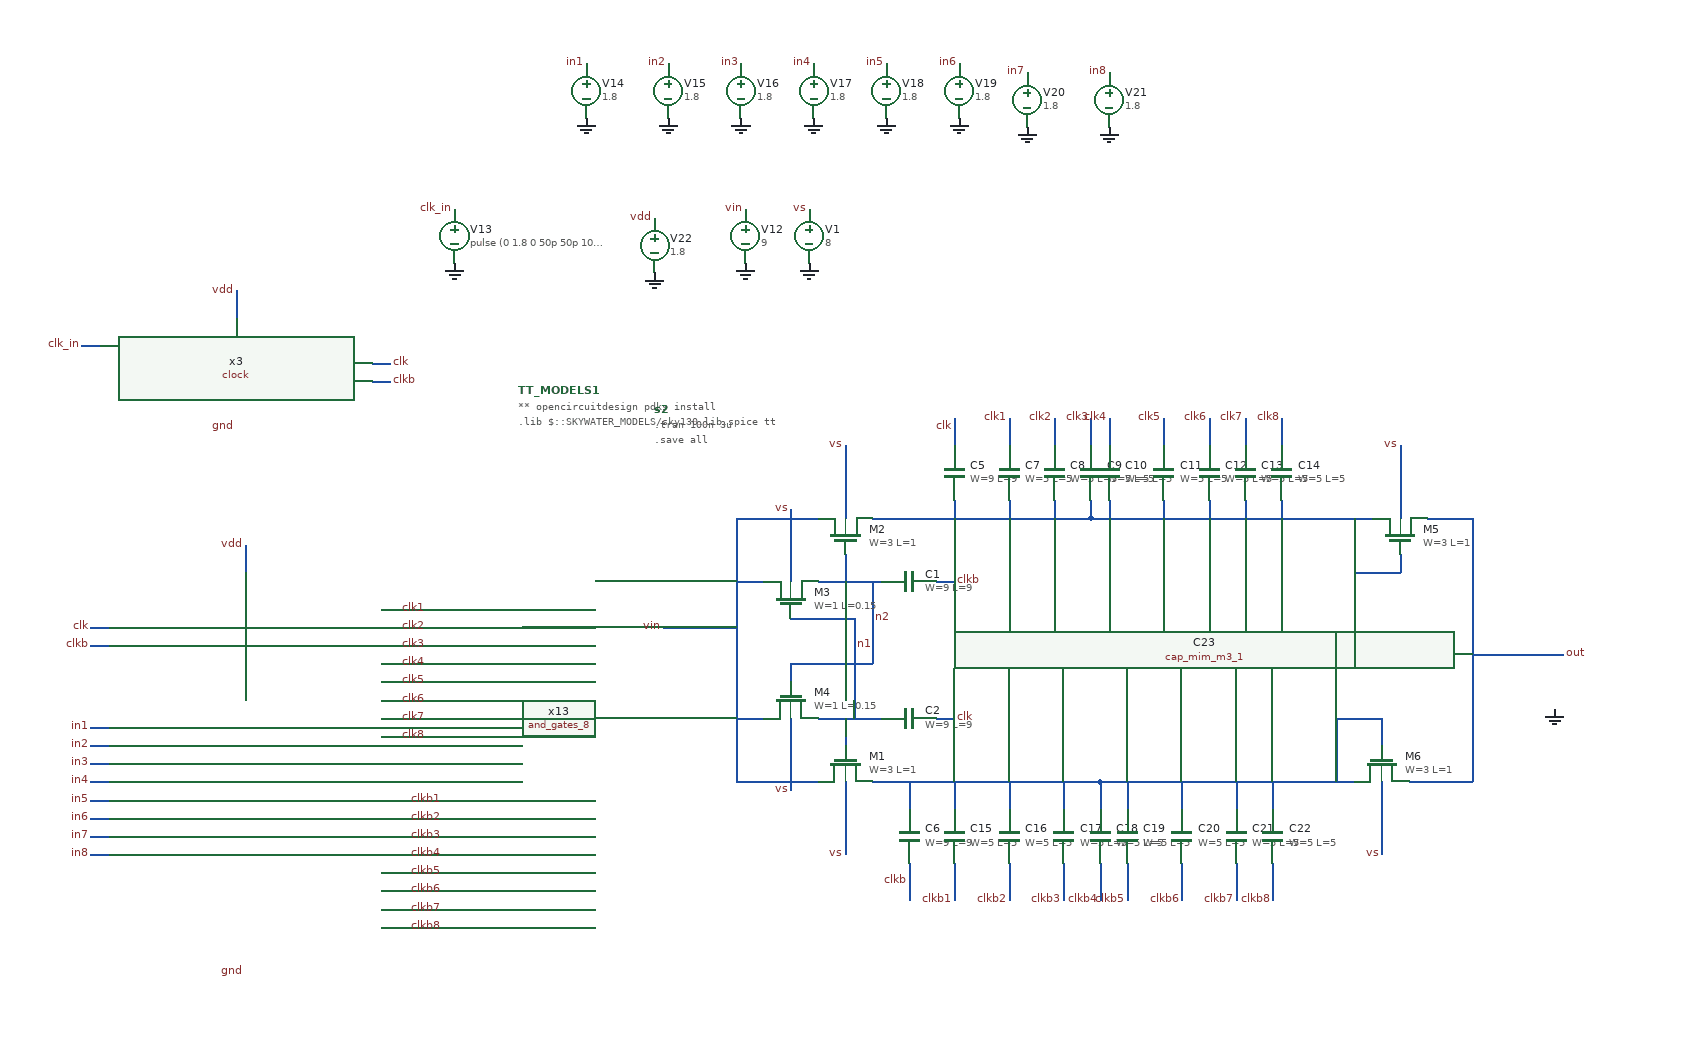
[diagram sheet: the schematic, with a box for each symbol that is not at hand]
v {xschem version=3.4.4 file_version=1.2
}
G {}
K {}
V {}
S {}
E {}
N -100 -80 140 -80 {
lab=#net1}
N -250 -80 -160 -80 {
lab=vin}
N -250 -80 -250 210 {
lab=vin}
N -250 210 -160 210 {
lab=vin}
N -100 210 150 210 {
lab=#net2}
N -250 -10 -220 -10 {
lab=vin}
N -250 140 -220 140 {
lab=vin}
N -160 -10 -90 -10 {
lab=n2}
N -130 -40 -130 -10 {
lab=n2}
N -160 140 -90 140 {
lab=n1}
N -130 140 -130 170 {
lab=n1}
N -10 -100 -10 -80 {
lab=#net1}
N -60 210 -60 240 {
lab=#net2}
N -10 -190 -10 -160 {
lab=clk}
N -60 300 -60 340 {
lab=clkb}
N -30 140 -10 140 {
lab=clk}
N -30 -10 -10 -10 {
lab=clkb}
N -190 30 -120 30 {
lab=n1}
N -120 30 -120 140 {
lab=n1}
N -190 80 -190 100 {
lab=n2}
N -190 80 -100 80 {
lab=n2}
N -100 -10 -100 80 {
lab=n2}
N 140 -80 380 -80 {
lab=#net1}
N 150 210 390 210 {
lab=#net2}
N 50 -100 50 -80 {
lab=#net1}
N 50 -190 50 -160 {
lab=clk1}
N 100 -100 100 -80 {
lab=#net1}
N 100 -190 100 -160 {
lab=clk2}
N 140 -100 140 -80 {
lab=#net1}
N 140 -190 140 -160 {
lab=clk3}
N 160 -100 160 -80 {
lab=#net1}
N 160 -190 160 -160 {
lab=clk4}
N 220 -100 220 -80 {
lab=#net1}
N 220 -190 220 -160 {
lab=clk5}
N 270 -100 270 -80 {
lab=#net1}
N 270 -190 270 -160 {
lab=clk6}
N 310 -100 310 -80 {
lab=#net1}
N 310 -190 310 -160 {
lab=clk7}
N 350 -100 350 -80 {
lab=#net1}
N 350 -190 350 -160 {
lab=clk8}
N -10 210 -10 240 {
lab=#net2}
N -10 300 -10 340 {
lab=clkb1}
N 50 210 50 240 {
lab=#net2}
N 50 300 50 340 {
lab=clkb2}
N 110 210 110 240 {
lab=#net2}
N 110 300 110 340 {
lab=clkb3}
N 150 210 150 240 {
lab=#net2}
N 150 300 150 340 {
lab=clkb4}
N 180 210 180 240 {
lab=#net2}
N 180 300 180 340 {
lab=clkb5}
N 240 210 240 240 {
lab=#net2}
N 240 300 240 340 {
lab=clkb6}
N 300 210 300 240 {
lab=#net2}
N 300 300 300 340 {
lab=clkb7}
N 340 210 340 240 {
lab=#net2}
N 340 300 340 340 {
lab=clkb8}
N -330 40 -250 40 {
lab=vin}
N 570 70 660 70 {
lab=out}
N -640 20 -620 20 {
lab=clk1}
N -640 40 -620 40 {
lab=clk2}
N -640 60 -620 60 {
lab=clk3}
N -640 80 -620 80 {
lab=clk4}
N -640 100 -620 100 {
lab=clk5}
N -640 120 -620 120 {
lab=clk6}
N -640 140 -620 140 {
lab=clk7}
N -640 160 -620 160 {
lab=clk8}
N -640 230 -610 230 {
lab=clkb1}
N -640 250 -610 250 {
lab=clkb2}
N -640 270 -610 270 {
lab=clkb3}
N -640 290 -610 290 {
lab=clkb4}
N -640 310 -610 310 {
lab=clkb5}
N -640 330 -610 330 {
lab=clkb6}
N -640 350 -610 350 {
lab=clkb7}
N -640 370 -610 370 {
lab=clkb8}
N -960 40 -940 40 {
lab=clk}
N -960 60 -940 60 {
lab=clkb}
N -960 150 -940 150 {
lab=in1}
N -960 170 -940 170 {
lab=in2}
N -960 190 -940 190 {
lab=in3}
N -960 210 -940 210 {
lab=in4}
N -960 230 -940 230 {
lab=in5}
N -960 250 -940 250 {
lab=in6}
N -960 270 -940 270 {
lab=in7}
N -960 290 -940 290 {
lab=in8}
N -790 -50 -790 -20 {
lab=vdd}
N -800 -330 -800 -300 {
lab=vdd}
N -970 -270 -950 -270 {
lab=clk_in}
N -650 -250 -630 -250 {
lab=clk}
N -650 -230 -630 -230 {
lab=clkb}
N 420 -80 450 -80 {
lab=#net1}
N 480 -40 480 -20 {
lab=#net1}
N 430 -20 480 -20 {
lab=#net1}
N 430 -80 430 -20 {
lab=#net1}
N 460 140 460 170 {
lab=#net2}
N 380 -80 420 -80 {
lab=#net1}
N 510 -80 560 -80 {
lab=out}
N 560 -80 560 210 {
lab=out}
N 490 210 560 210 {
lab=out}
N 390 210 430 210 {
lab=#net2}
N 410 140 460 140 {
lab=#net2}
N 410 140 410 210 {
lab=#net2}
N 560 70 570 70 {
lab=out}
N 480 -160 480 -80 {
lab=vs}
N -130 -160 -130 -80 {
lab=vs}
N -190 -90 -190 -10 {
lab=vs}
N -190 140 -190 220 {
lab=vs}
N -130 210 -130 290 {
lab=vs}
N 460 210 460 290 {
lab=vs}
C {sky130_fd_pr/nfet_01v8.sym} -130 -60 1 1 {name=M2
L=1
W=3
nf=1 
mult=1
ad="'int((nf+1)/2) * W/nf * 0.29'" 
pd="'2*int((nf+1)/2) * (W/nf + 0.29)'"
as="'int((nf+2)/2) * W/nf * 0.29'" 
ps="'2*int((nf+2)/2) * (W/nf + 0.29)'"
nrd="'0.29 / W'" nrs="'0.29 / W'"
sa=0 sb=0 sd=0
model=nfet_01v8
spiceprefix=X
}
C {sky130_fd_pr/nfet_01v8.sym} -130 190 1 0 {name=M1
L=1
W=3
nf=1 
mult=1
ad="'int((nf+1)/2) * W/nf * 0.29'" 
pd="'2*int((nf+1)/2) * (W/nf + 0.29)'"
as="'int((nf+2)/2) * W/nf * 0.29'" 
ps="'2*int((nf+2)/2) * (W/nf + 0.29)'"
nrd="'0.29 / W'" nrs="'0.29 / W'"
sa=0 sb=0 sd=0
model=nfet_01v8
spiceprefix=X
}
C {sky130_fd_pr/nfet_01v8.sym} -190 10 1 1 {name=M3
L=0.15
W=1
nf=1 
mult=1
ad="'int((nf+1)/2) * W/nf * 0.29'" 
pd="'2*int((nf+1)/2) * (W/nf + 0.29)'"
as="'int((nf+2)/2) * W/nf * 0.29'" 
ps="'2*int((nf+2)/2) * (W/nf + 0.29)'"
nrd="'0.29 / W'" nrs="'0.29 / W'"
sa=0 sb=0 sd=0
model=nfet_01v8
spiceprefix=X
}
C {sky130_fd_pr/nfet_01v8.sym} -190 120 1 0 {name=M4
L=0.15
W=1
nf=1 
mult=1
ad="'int((nf+1)/2) * W/nf * 0.29'" 
pd="'2*int((nf+1)/2) * (W/nf + 0.29)'"
as="'int((nf+2)/2) * W/nf * 0.29'" 
ps="'2*int((nf+2)/2) * (W/nf + 0.29)'"
nrd="'0.29 / W'" nrs="'0.29 / W'"
sa=0 sb=0 sd=0
model=nfet_01v8
spiceprefix=X
}
C {sky130_fd_pr/cap_mim_m3_1.sym} -60 -10 3 0 {name=C1 model=cap_mim_m3_1 W=9 L=9 MF=1 spiceprefix=X}
C {sky130_fd_pr/cap_mim_m3_1.sym} -60 140 3 0 {name=C2 model=cap_mim_m3_1 W=9 L=9 MF=1 spiceprefix=X}
C {sky130_fd_pr/cap_mim_m3_1.sym} -10 -130 2 0 {name=C5 model=cap_mim_m3_1 W=9 L=9 MF=1 spiceprefix=X}
C {sky130_fd_pr/cap_mim_m3_1.sym} -60 270 0 0 {name=C6 model=cap_mim_m3_1 W=9 L=9 MF=1 spiceprefix=X}
C {sky130_fd_pr/cap_mim_m3_1.sym} 50 -130 2 0 {name=C7 model=cap_mim_m3_1 W=5 L=5 MF=1 spiceprefix=X}
C {sky130_fd_pr/cap_mim_m3_1.sym} 100 -130 2 0 {name=C8 model=cap_mim_m3_1 W=5 L=5 MF=1 spiceprefix=X}
C {sky130_fd_pr/cap_mim_m3_1.sym} 140 -130 2 0 {name=C9 model=cap_mim_m3_1 W=5 L=5 MF=1 spiceprefix=X}
C {sky130_fd_pr/cap_mim_m3_1.sym} 160 -130 2 0 {name=C10 model=cap_mim_m3_1 W=5 L=5 MF=1 spiceprefix=X}
C {sky130_fd_pr/cap_mim_m3_1.sym} 220 -130 2 0 {name=C11 model=cap_mim_m3_1 W=5 L=5 MF=1 spiceprefix=X}
C {sky130_fd_pr/cap_mim_m3_1.sym} 270 -130 2 0 {name=C12 model=cap_mim_m3_1 W=5 L=5 MF=1 spiceprefix=X}
C {sky130_fd_pr/cap_mim_m3_1.sym} 310 -130 2 0 {name=C13 model=cap_mim_m3_1 W=5 L=5 MF=1 spiceprefix=X}
C {sky130_fd_pr/cap_mim_m3_1.sym} 350 -130 2 0 {name=C14 model=cap_mim_m3_1 W=5 L=5 MF=1 spiceprefix=X}
C {sky130_fd_pr/cap_mim_m3_1.sym} -10 270 0 0 {name=C15 model=cap_mim_m3_1 W=5 L=5 MF=1 spiceprefix=X}
C {sky130_fd_pr/cap_mim_m3_1.sym} 50 270 0 0 {name=C16 model=cap_mim_m3_1 W=5 L=5 MF=1 spiceprefix=X}
C {sky130_fd_pr/cap_mim_m3_1.sym} 110 270 0 0 {name=C17 model=cap_mim_m3_1 W=5 L=5 MF=1 spiceprefix=X}
C {sky130_fd_pr/cap_mim_m3_1.sym} 150 270 0 0 {name=C18 model=cap_mim_m3_1 W=5 L=5 MF=1 spiceprefix=X}
C {sky130_fd_pr/cap_mim_m3_1.sym} 180 270 0 0 {name=C19 model=cap_mim_m3_1 W=5 L=5 MF=1 spiceprefix=X}
C {sky130_fd_pr/cap_mim_m3_1.sym} 240 270 0 0 {name=C20 model=cap_mim_m3_1 W=5 L=5 MF=1 spiceprefix=X}
C {sky130_fd_pr/cap_mim_m3_1.sym} 300 270 0 0 {name=C21 model=cap_mim_m3_1 W=5 L=5 MF=1 spiceprefix=X}
C {sky130_fd_pr/cap_mim_m3_1.sym} 340 270 0 0 {name=C22 model=cap_mim_m3_1 W=5 L=5 MF=1 spiceprefix=X}
C {devices/lab_pin.sym} -10 -10 2 0 {name=p2 sig_type=std_logic lab=clkb}
C {devices/lab_pin.sym} -10 140 2 0 {name=p3 sig_type=std_logic lab=clk}
C {devices/lab_pin.sym} -10 -180 0 0 {name=p7 sig_type=std_logic lab=clk}
C {devices/lab_pin.sym} -60 320 0 0 {name=p6 sig_type=std_logic lab=clkb}
C {and_gates_8.sym} -790 200 0 0 {name=x13}
C {devices/lab_pin.sym} -620 20 2 0 {name=p238 sig_type=std_logic lab=clk1}
C {devices/lab_pin.sym} -620 40 2 0 {name=p239 sig_type=std_logic lab=clk2}
C {devices/lab_pin.sym} -620 60 2 0 {name=p240 sig_type=std_logic lab=clk3}
C {devices/lab_pin.sym} -620 80 2 0 {name=p241 sig_type=std_logic lab=clk4}
C {devices/lab_pin.sym} -620 100 2 0 {name=p242 sig_type=std_logic lab=clk5}
C {devices/lab_pin.sym} -620 120 2 0 {name=p243 sig_type=std_logic lab=clk6}
C {devices/lab_pin.sym} -620 140 2 0 {name=p244 sig_type=std_logic lab=clk7}
C {devices/lab_pin.sym} -620 160 2 0 {name=p245 sig_type=std_logic lab=clk8}
C {devices/lab_pin.sym} -610 230 0 1 {name=p246 sig_type=std_logic lab=clkb1}
C {devices/lab_pin.sym} -610 250 0 1 {name=p247 sig_type=std_logic lab=clkb2}
C {devices/lab_pin.sym} -610 270 0 1 {name=p248 sig_type=std_logic lab=clkb3}
C {devices/lab_pin.sym} -610 290 0 1 {name=p249 sig_type=std_logic lab=clkb4}
C {devices/lab_pin.sym} -610 310 0 1 {name=p250 sig_type=std_logic lab=clkb5}
C {devices/lab_pin.sym} -610 330 0 1 {name=p251 sig_type=std_logic lab=clkb6}
C {devices/lab_pin.sym} -610 350 0 1 {name=p252 sig_type=std_logic lab=clkb7}
C {devices/lab_pin.sym} -610 370 0 1 {name=p253 sig_type=std_logic lab=clkb8}
C {devices/lab_pin.sym} -960 40 0 0 {name=p254 sig_type=std_logic lab=clk}
C {devices/lab_pin.sym} -960 60 0 0 {name=p255 sig_type=std_logic lab=clkb}
C {devices/lab_pin.sym} -960 150 0 0 {name=p256 sig_type=std_logic lab=in1}
C {devices/lab_pin.sym} -960 170 0 0 {name=p257 sig_type=std_logic lab=in2}
C {devices/lab_pin.sym} -960 190 0 0 {name=p258 sig_type=std_logic lab=in3}
C {devices/lab_pin.sym} -960 210 0 0 {name=p259 sig_type=std_logic lab=in4}
C {devices/lab_pin.sym} -960 230 0 0 {name=p260 sig_type=std_logic lab=in5}
C {devices/lab_pin.sym} -960 250 0 0 {name=p261 sig_type=std_logic lab=in6}
C {devices/lab_pin.sym} -960 270 0 0 {name=p262 sig_type=std_logic lab=in7}
C {devices/lab_pin.sym} -960 290 0 0 {name=p263 sig_type=std_logic lab=in8}
C {devices/lab_pin.sym} -790 -50 1 0 {name=p264 sig_type=std_logic lab=vdd}
C {devices/lab_pin.sym} -800 -330 1 0 {name=p27 sig_type=std_logic lab=vdd}
C {devices/lab_pin.sym} -970 -270 0 0 {name=p28 sig_type=std_logic lab=clk_in}
C {devices/lab_pin.sym} -630 -250 2 0 {name=p29 sig_type=std_logic lab=clk}
C {devices/lab_pin.sym} -630 -230 2 0 {name=p30 sig_type=std_logic lab=clkb}
C {clock.sym} -800 -240 0 0 {name=x3}
C {devices/lab_pin.sym} -800 -180 3 0 {name=p31 sig_type=std_logic lab=gnd}
C {devices/lab_pin.sym} -790 420 3 0 {name=p32 sig_type=std_logic lab=gnd}
C {devices/vsource.sym} -240 -390 0 0 {name=V12 value=9}
C {devices/lab_pin.sym} -240 -420 1 0 {name=p33 sig_type=std_logic lab=vin}
C {devices/gnd.sym} -240 -360 0 0 {name=l1 lab=GND}
C {devices/vsource.sym} -560 -390 0 0 {name=V13 value="pulse (0 1.8 0 50p 50p 10n 20n)"}
C {devices/lab_pin.sym} -560 -420 1 0 {name=p34 sig_type=std_logic lab=clk_in}
C {devices/gnd.sym} -560 -360 0 0 {name=l13 lab=GND}
C {devices/vsource.sym} -415 -550 0 0 {name=V14 value=1.8}
C {devices/lab_pin.sym} -415 -580 1 0 {name=p35 sig_type=std_logic lab=in1
value=1.8}
C {devices/gnd.sym} -415 -520 0 0 {name=l14 lab=GND
value=0}
C {devices/vsource.sym} -325 -550 0 0 {name=V15 value=1.8}
C {devices/lab_pin.sym} -325 -580 1 0 {name=p36 sig_type=std_logic lab=in2
value=1.8}
C {devices/gnd.sym} -325 -520 0 0 {name=l15 lab=GND
value=0}
C {devices/vsource.sym} -245 -550 0 0 {name=V16 value=1.8}
C {devices/lab_pin.sym} -245 -580 1 0 {name=p37 sig_type=std_logic lab=in3
value=1.8}
C {devices/gnd.sym} -245 -520 0 0 {name=l16 lab=GND
value=0}
C {devices/vsource.sym} -165 -550 0 0 {name=V17 value=1.8}
C {devices/lab_pin.sym} -165 -580 1 0 {name=p38 sig_type=std_logic lab=in4
value=1.8}
C {devices/gnd.sym} -165 -520 0 0 {name=l17 lab=GND
value=0}
C {devices/vsource.sym} -85 -550 0 0 {name=V18 value=1.8
}
C {devices/lab_pin.sym} -85 -580 1 0 {name=p39 sig_type=std_logic lab=in5
value=1.8}
C {devices/gnd.sym} -85 -520 0 0 {name=l18 lab=GND
value=1.8}
C {devices/vsource.sym} -5 -550 0 0 {name=V19 value=1.8}
C {devices/lab_pin.sym} -5 -580 1 0 {name=p40 sig_type=std_logic lab=in6
value=1.8}
C {devices/gnd.sym} -5 -520 0 0 {name=l19 lab=GND
value=1.8}
C {devices/vsource.sym} 70 -540 0 0 {name=V20 value=1.8}
C {devices/lab_pin.sym} 70 -570 1 0 {name=p41 sig_type=std_logic lab=in7
value=1.8}
C {devices/gnd.sym} 70 -510 0 0 {name=l20 lab=GND
value=1.8}
C {devices/vsource.sym} 160 -540 0 0 {name=V21 value=1.8}
C {devices/lab_pin.sym} 160 -570 1 0 {name=p42 sig_type=std_logic lab=in8
value=1.8}
C {devices/gnd.sym} 160 -510 0 0 {name=l21 lab=GND
value=1.8}
C {devices/vsource.sym} -340 -380 0 0 {name=V22 value=1.8}
C {devices/lab_pin.sym} -340 -410 1 0 {name=p43 sig_type=std_logic lab=vdd}
C {devices/gnd.sym} -340 -350 0 0 {name=l22 lab=GND}
C {devices/code.sym} -490 -220 0 0 {name=TT_MODELS1
only_toplevel=true
format="tcleval( @value )"
value="
** opencircuitdesign pdks install
.lib $::SKYWATER_MODELS/sky130.lib.spice tt

"
spice_ignore=false}
C {devices/code_shown.sym} -340 -200 0 0 {name=s2 only_toplevel=false value="
.tran 100n 3u
.save all
"}
C {devices/lab_pin.sym} -330 40 0 0 {name=p5 sig_type=std_logic lab=vin}
C {devices/lab_pin.sym} 50 -190 1 0 {name=p8 sig_type=std_logic lab=clk1}
C {devices/lab_pin.sym} 100 -190 1 0 {name=p9 sig_type=std_logic lab=clk2}
C {devices/lab_pin.sym} 140 -190 1 0 {name=p10 sig_type=std_logic lab=clk3}
C {devices/lab_pin.sym} 160 -190 1 0 {name=p11 sig_type=std_logic lab=clk4}
C {devices/lab_pin.sym} 220 -190 1 0 {name=p12 sig_type=std_logic lab=clk5}
C {devices/lab_pin.sym} 270 -190 1 0 {name=p13 sig_type=std_logic lab=clk6}
C {devices/lab_pin.sym} 310 -190 1 0 {name=p14 sig_type=std_logic lab=clk7}
C {devices/lab_pin.sym} 350 -190 1 0 {name=p15 sig_type=std_logic lab=clk8}
C {devices/lab_pin.sym} -10 340 3 0 {name=p16 sig_type=std_logic lab=clkb1}
C {devices/lab_pin.sym} 50 340 3 0 {name=p17 sig_type=std_logic lab=clkb2}
C {devices/lab_pin.sym} 110 340 3 0 {name=p18 sig_type=std_logic lab=clkb3}
C {devices/lab_pin.sym} 150 340 3 0 {name=p19 sig_type=std_logic lab=clkb4}
C {devices/lab_pin.sym} 180 340 3 0 {name=p20 sig_type=std_logic lab=clkb5}
C {devices/lab_pin.sym} 240 340 3 0 {name=p21 sig_type=std_logic lab=clkb6}
C {devices/lab_pin.sym} 300 340 3 0 {name=p22 sig_type=std_logic lab=clkb7}
C {devices/lab_pin.sym} 340 340 3 0 {name=p23 sig_type=std_logic lab=clkb8}
C {devices/lab_pin.sym} 660 70 2 0 {name=p154 sig_type=std_logic lab=out}
C {sky130_fd_pr/cap_mim_m3_1.sym} 650 100 0 0 {name=C23 model=cap_mim_m3_1 W=23 L=23 MF=1 spiceprefix=X}
C {devices/gnd.sym} 650 130 0 0 {name=l36 lab=GND}
C {devices/lab_pin.sym} -100 30 2 0 {name=p24 sig_type=std_logic lab=n2}
C {devices/lab_pin.sym} -120 60 2 0 {name=p25 sig_type=std_logic lab=n1}
C {sky130_fd_pr/nfet_01v8_lvt.sym} 480 -60 1 1 {name=M5
L=1
W=3
nf=1
mult=1
ad="'int((nf+1)/2) * W/nf * 0.29'" 
pd="'2*int((nf+1)/2) * (W/nf + 0.29)'"
as="'int((nf+2)/2) * W/nf * 0.29'" 
ps="'2*int((nf+2)/2) * (W/nf + 0.29)'"
nrd="'0.29 / W'" nrs="'0.29 / W'"
sa=0 sb=0 sd=0
model=nfet_01v8_lvt
spiceprefix=X
}
C {sky130_fd_pr/nfet_01v8_lvt.sym} 460 190 1 0 {name=M6
L=1
W=3
nf=1
mult=1
ad="'int((nf+1)/2) * W/nf * 0.29'" 
pd="'2*int((nf+1)/2) * (W/nf + 0.29)'"
as="'int((nf+2)/2) * W/nf * 0.29'" 
ps="'2*int((nf+2)/2) * (W/nf + 0.29)'"
nrd="'0.29 / W'" nrs="'0.29 / W'"
sa=0 sb=0 sd=0
model=nfet_01v8_lvt
spiceprefix=X
}
C {devices/lab_pin.sym} 480 -160 1 0 {name=p1 sig_type=std_logic lab=vs}
C {devices/lab_pin.sym} -130 -160 1 0 {name=p4 sig_type=std_logic lab=vs}
C {devices/lab_pin.sym} -190 -90 1 0 {name=p26 sig_type=std_logic lab=vs}
C {devices/lab_pin.sym} -190 220 3 0 {name=p44 sig_type=std_logic lab=vs}
C {devices/lab_pin.sym} -130 290 3 0 {name=p45 sig_type=std_logic lab=vs}
C {devices/lab_pin.sym} 460 290 3 0 {name=p46 sig_type=std_logic lab=vs}
C {devices/vsource.sym} -170 -390 0 0 {name=V1 value=8}
C {devices/lab_pin.sym} -170 -420 1 0 {name=p47 sig_type=std_logic lab=vs}
C {devices/gnd.sym} -170 -360 0 0 {name=l2 lab=GND}
